VERSION 5.7 ;
  NOWIREEXTENSIONATPIN ON ;
  DIVIDERCHAR "/" ;
  BUSBITCHARS "[]" ;
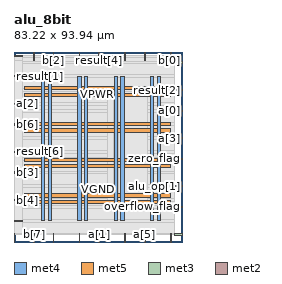
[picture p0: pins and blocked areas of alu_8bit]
MACRO alu_8bit
  CLASS BLOCK ;
  FOREIGN alu_8bit ;
  ORIGIN 0.000 0.000 ;
  SIZE 83.220 BY 93.940 ;
  PIN VGND
    DIRECTION INOUT ;
    USE GROUND ;
    PORT
      LAYER met4 ;
        RECT 16.990 10.640 18.590 81.840 ;
    END
    PORT
      LAYER met4 ;
        RECT 34.930 10.640 36.530 81.840 ;
    END
    PORT
      LAYER met4 ;
        RECT 52.870 10.640 54.470 81.840 ;
    END
    PORT
      LAYER met4 ;
        RECT 70.810 10.640 72.410 81.840 ;
    END
    PORT
      LAYER met5 ;
        RECT 5.280 22.220 77.520 23.820 ;
    END
    PORT
      LAYER met5 ;
        RECT 5.280 39.900 77.520 41.500 ;
    END
    PORT
      LAYER met5 ;
        RECT 5.280 57.580 77.520 59.180 ;
    END
    PORT
      LAYER met5 ;
        RECT 5.280 75.260 77.520 76.860 ;
    END
  END VGND
  PIN VPWR
    DIRECTION INOUT ;
    USE POWER ;
    PORT
      LAYER met4 ;
        RECT 13.690 10.640 15.290 81.840 ;
    END
    PORT
      LAYER met4 ;
        RECT 31.630 10.640 33.230 81.840 ;
    END
    PORT
      LAYER met4 ;
        RECT 49.570 10.640 51.170 81.840 ;
    END
    PORT
      LAYER met4 ;
        RECT 67.510 10.640 69.110 81.840 ;
    END
    PORT
      LAYER met5 ;
        RECT 5.280 18.920 77.520 20.520 ;
    END
    PORT
      LAYER met5 ;
        RECT 5.280 36.600 77.520 38.200 ;
    END
    PORT
      LAYER met5 ;
        RECT 5.280 54.280 77.520 55.880 ;
    END
    PORT
      LAYER met5 ;
        RECT 5.280 71.960 77.520 73.560 ;
    END
  END VPWR
  PIN a[0]
    DIRECTION INPUT ;
    USE SIGNAL ;
    ANTENNAGATEAREA 0.196500 ;
    PORT
      LAYER met3 ;
        RECT 79.220 64.640 83.220 65.240 ;
    END
  END a[0]
  PIN a[1]
    DIRECTION INPUT ;
    USE SIGNAL ;
    ANTENNAGATEAREA 0.213000 ;
    PORT
      LAYER met2 ;
        RECT 41.950 0.000 42.230 4.000 ;
    END
  END a[1]
  PIN a[2]
    DIRECTION INPUT ;
    USE SIGNAL ;
    ANTENNAGATEAREA 0.196500 ;
    PORT
      LAYER met3 ;
        RECT 0.000 68.040 4.000 68.640 ;
    END
  END a[2]
  PIN a[3]
    DIRECTION INPUT ;
    USE SIGNAL ;
    ANTENNAGATEAREA 0.126000 ;
    PORT
      LAYER met3 ;
        RECT 79.220 51.040 83.220 51.640 ;
    END
  END a[3]
  PIN a[4]
    DIRECTION INPUT ;
    USE SIGNAL ;
    ANTENNAGATEAREA 0.213000 ;
    PORT
      LAYER met2 ;
        RECT 54.830 89.940 55.110 93.940 ;
    END
  END a[4]
  PIN a[5]
    DIRECTION INPUT ;
    USE SIGNAL ;
    ANTENNAGATEAREA 0.196500 ;
    PORT
      LAYER met2 ;
        RECT 64.490 0.000 64.770 4.000 ;
    END
  END a[5]
  PIN a[6]
    DIRECTION INPUT ;
    USE SIGNAL ;
    ANTENNAGATEAREA 0.196500 ;
    PORT
      LAYER met3 ;
        RECT 0.000 10.240 4.000 10.840 ;
    END
  END a[6]
  PIN a[7]
    DIRECTION INPUT ;
    USE SIGNAL ;
    ANTENNAGATEAREA 0.213000 ;
    PORT
      LAYER met3 ;
        RECT 79.220 88.440 83.220 89.040 ;
    END
  END a[7]
  PIN alu_op[0]
    DIRECTION INPUT ;
    USE SIGNAL ;
    ANTENNAGATEAREA 0.159000 ;
    PORT
      LAYER met2 ;
        RECT 64.490 89.940 64.770 93.940 ;
    END
  END alu_op[0]
  PIN alu_op[1]
    DIRECTION INPUT ;
    USE SIGNAL ;
    ANTENNAGATEAREA 0.213000 ;
    PORT
      LAYER met3 ;
        RECT 79.220 27.240 83.220 27.840 ;
    END
  END alu_op[1]
  PIN alu_op[2]
    DIRECTION INPUT ;
    USE SIGNAL ;
    ANTENNAGATEAREA 0.213000 ;
    PORT
      LAYER met2 ;
        RECT 0.090 0.000 0.370 4.000 ;
    END
  END alu_op[2]
  PIN alu_op[3]
    DIRECTION INPUT ;
    USE SIGNAL ;
    ANTENNAGATEAREA 0.196500 ;
    PORT
      LAYER met2 ;
        RECT 77.370 0.000 77.650 4.000 ;
    END
  END alu_op[3]
  PIN b[0]
    DIRECTION INPUT ;
    USE SIGNAL ;
    ANTENNAGATEAREA 0.159000 ;
    PORT
      LAYER met2 ;
        RECT 77.370 89.940 77.650 93.940 ;
    END
  END b[0]
  PIN b[1]
    DIRECTION INPUT ;
    USE SIGNAL ;
    ANTENNAGATEAREA 0.213000 ;
    PORT
      LAYER met2 ;
        RECT 19.410 0.000 19.690 4.000 ;
    END
  END b[1]
  PIN b[2]
    DIRECTION INPUT ;
    USE SIGNAL ;
    ANTENNAGATEAREA 0.196500 ;
    PORT
      LAYER met2 ;
        RECT 19.410 89.940 19.690 93.940 ;
    END
  END b[2]
  PIN b[3]
    DIRECTION INPUT ;
    USE SIGNAL ;
    ANTENNAGATEAREA 0.213000 ;
    PORT
      LAYER met3 ;
        RECT 0.000 34.040 4.000 34.640 ;
    END
  END b[3]
  PIN b[4]
    DIRECTION INPUT ;
    USE SIGNAL ;
    ANTENNAGATEAREA 0.159000 ;
    PORT
      LAYER met3 ;
        RECT 0.000 20.440 4.000 21.040 ;
    END
  END b[4]
  PIN b[5]
    DIRECTION INPUT ;
    USE SIGNAL ;
    ANTENNAGATEAREA 0.126000 ;
    PORT
      LAYER met3 ;
        RECT 79.220 3.440 83.220 4.040 ;
    END
  END b[5]
  PIN b[6]
    DIRECTION INPUT ;
    USE SIGNAL ;
    ANTENNAGATEAREA 0.159000 ;
    PORT
      LAYER met3 ;
        RECT 0.000 57.840 4.000 58.440 ;
    END
  END b[6]
  PIN b[7]
    DIRECTION INPUT ;
    USE SIGNAL ;
    ANTENNAGATEAREA 0.213000 ;
    PORT
      LAYER met2 ;
        RECT 9.750 0.000 10.030 4.000 ;
    END
  END b[7]
  PIN carry_flag
    DIRECTION OUTPUT TRISTATE ;
    USE SIGNAL ;
    ANTENNADIFFAREA 0.795200 ;
    PORT
      LAYER met2 ;
        RECT 9.750 89.940 10.030 93.940 ;
    END
  END carry_flag
  PIN overflow_flag
    DIRECTION OUTPUT TRISTATE ;
    USE SIGNAL ;
    ANTENNADIFFAREA 0.795200 ;
    PORT
      LAYER met3 ;
        RECT 79.220 17.040 83.220 17.640 ;
    END
  END overflow_flag
  PIN result[0]
    DIRECTION OUTPUT TRISTATE ;
    USE SIGNAL ;
    ANTENNADIFFAREA 0.795200 ;
    PORT
      LAYER met2 ;
        RECT 32.290 0.000 32.570 4.000 ;
    END
  END result[0]
  PIN result[1]
    DIRECTION OUTPUT TRISTATE ;
    USE SIGNAL ;
    ANTENNADIFFAREA 0.795200 ;
    PORT
      LAYER met3 ;
        RECT 0.000 81.640 4.000 82.240 ;
    END
  END result[1]
  PIN result[2]
    DIRECTION OUTPUT TRISTATE ;
    USE SIGNAL ;
    ANTENNADIFFAREA 0.795200 ;
    PORT
      LAYER met3 ;
        RECT 79.220 74.840 83.220 75.440 ;
    END
  END result[2]
  PIN result[3]
    DIRECTION OUTPUT TRISTATE ;
    USE SIGNAL ;
    ANTENNADIFFAREA 0.795200 ;
    PORT
      LAYER met2 ;
        RECT 32.290 89.940 32.570 93.940 ;
    END
  END result[3]
  PIN result[4]
    DIRECTION OUTPUT TRISTATE ;
    USE SIGNAL ;
    ANTENNADIFFAREA 0.795200 ;
    PORT
      LAYER met2 ;
        RECT 41.950 89.940 42.230 93.940 ;
    END
  END result[4]
  PIN result[5]
    DIRECTION OUTPUT TRISTATE ;
    USE SIGNAL ;
    ANTENNADIFFAREA 0.795200 ;
    PORT
      LAYER met2 ;
        RECT 54.830 0.000 55.110 4.000 ;
    END
  END result[5]
  PIN result[6]
    DIRECTION OUTPUT TRISTATE ;
    USE SIGNAL ;
    ANTENNADIFFAREA 0.795200 ;
    PORT
      LAYER met3 ;
        RECT 0.000 44.240 4.000 44.840 ;
    END
  END result[6]
  PIN result[7]
    DIRECTION OUTPUT TRISTATE ;
    USE SIGNAL ;
    ANTENNADIFFAREA 0.795200 ;
    PORT
      LAYER met3 ;
        RECT 0.000 91.840 4.000 92.440 ;
    END
  END result[7]
  PIN zero_flag
    DIRECTION OUTPUT TRISTATE ;
    USE SIGNAL ;
    ANTENNADIFFAREA 0.795200 ;
    PORT
      LAYER met3 ;
        RECT 79.220 40.840 83.220 41.440 ;
    END
  END zero_flag
  OBS
      LAYER li1 ;
        RECT 5.520 10.795 77.280 81.685 ;
      LAYER met1 ;
        RECT 0.070 10.640 77.670 81.840 ;
      LAYER met2 ;
        RECT 0.100 89.660 9.470 91.645 ;
        RECT 10.310 89.660 19.130 91.645 ;
        RECT 19.970 89.660 32.010 91.645 ;
        RECT 32.850 89.660 41.670 91.645 ;
        RECT 42.510 89.660 54.550 91.645 ;
        RECT 55.390 89.660 64.210 91.645 ;
        RECT 65.050 89.660 77.090 91.645 ;
        RECT 0.100 4.280 77.650 89.660 ;
        RECT 0.650 3.555 9.470 4.280 ;
        RECT 10.310 3.555 19.130 4.280 ;
        RECT 19.970 3.555 32.010 4.280 ;
        RECT 32.850 3.555 41.670 4.280 ;
        RECT 42.510 3.555 54.550 4.280 ;
        RECT 55.390 3.555 64.210 4.280 ;
        RECT 65.050 3.555 77.090 4.280 ;
      LAYER met3 ;
        RECT 4.400 91.440 79.220 92.290 ;
        RECT 4.000 89.440 79.220 91.440 ;
        RECT 4.000 88.040 78.820 89.440 ;
        RECT 4.000 82.640 79.220 88.040 ;
        RECT 4.400 81.240 79.220 82.640 ;
        RECT 4.000 75.840 79.220 81.240 ;
        RECT 4.000 74.440 78.820 75.840 ;
        RECT 4.000 69.040 79.220 74.440 ;
        RECT 4.400 67.640 79.220 69.040 ;
        RECT 4.000 65.640 79.220 67.640 ;
        RECT 4.000 64.240 78.820 65.640 ;
        RECT 4.000 58.840 79.220 64.240 ;
        RECT 4.400 57.440 79.220 58.840 ;
        RECT 4.000 52.040 79.220 57.440 ;
        RECT 4.000 50.640 78.820 52.040 ;
        RECT 4.000 45.240 79.220 50.640 ;
        RECT 4.400 43.840 79.220 45.240 ;
        RECT 4.000 41.840 79.220 43.840 ;
        RECT 4.000 40.440 78.820 41.840 ;
        RECT 4.000 35.040 79.220 40.440 ;
        RECT 4.400 33.640 79.220 35.040 ;
        RECT 4.000 28.240 79.220 33.640 ;
        RECT 4.000 26.840 78.820 28.240 ;
        RECT 4.000 21.440 79.220 26.840 ;
        RECT 4.400 20.040 79.220 21.440 ;
        RECT 4.000 18.040 79.220 20.040 ;
        RECT 4.000 16.640 78.820 18.040 ;
        RECT 4.000 11.240 79.220 16.640 ;
        RECT 4.400 9.840 79.220 11.240 ;
        RECT 4.000 4.440 79.220 9.840 ;
        RECT 4.000 3.575 78.820 4.440 ;
      LAYER met4 ;
        RECT 46.295 19.895 49.170 74.625 ;
        RECT 51.570 19.895 52.470 74.625 ;
        RECT 54.870 19.895 65.945 74.625 ;
  END
END alu_8bit
END LIBRARY

